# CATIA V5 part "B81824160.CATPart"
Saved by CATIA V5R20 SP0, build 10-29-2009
Part number: B81824160
Revision: 4
Definition: design
Nomenclature: B81824160
Source: made
Description: NOT SPECIFIED
Bounding box of the stored display mesh (mm): x -14 to 14, y -14 to 14, z 0 to 160
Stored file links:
  C:\Users\Raffaele\Desktop\3D X SITO CF\BOLEX\6-PILLAR REF 818\B81824160.CATPart

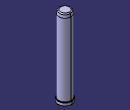
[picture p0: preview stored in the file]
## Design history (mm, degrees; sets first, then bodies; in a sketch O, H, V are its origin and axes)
Body1 "MANIFOLD_SOLID_BREP #370" (main body)
  Solid1: solid without history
